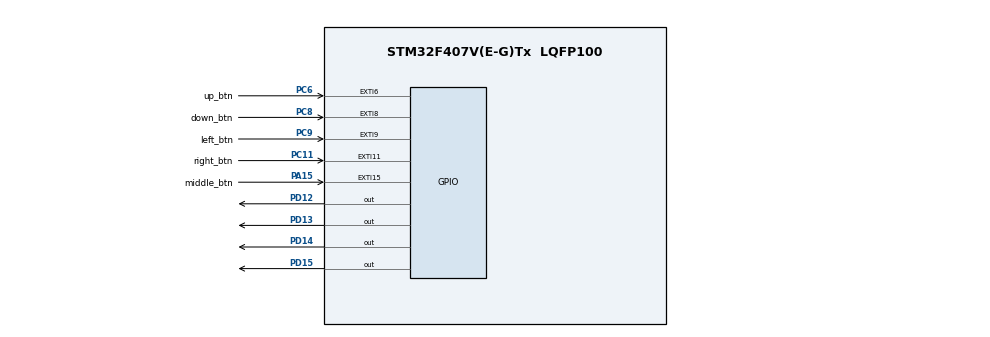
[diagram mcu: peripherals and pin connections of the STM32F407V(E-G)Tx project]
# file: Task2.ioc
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Mcu.Family=STM32F4
Mcu.Name=STM32F407V(E-G)Tx
Mcu.Package=LQFP100
NVIC.EXTI15_10_IRQn=true\:0\:0\:false\:false\:true\:true\:true
NVIC.EXTI9_5_IRQn=true\:0\:0\:false\:false\:true\:true\:true
NVIC.PriorityGroup=NVIC_PRIORITYGROUP_4
PA15.GPIO_Label=middle_btn
PA15.GPIO_ModeDefaultEXTI=GPIO_MODE_IT_FALLING
PA15.Signal=GPXTI15
PC11.GPIO_Label=right_btn
PC11.GPIO_ModeDefaultEXTI=GPIO_MODE_IT_FALLING
PC11.Signal=GPXTI11
PC6.GPIO_Label=up_btn
PC6.GPIO_ModeDefaultEXTI=GPIO_MODE_IT_FALLING
PC6.Signal=GPXTI6
PC8.GPIO_Label=down_btn
PC8.GPIO_ModeDefaultEXTI=GPIO_MODE_IT_FALLING
PC8.Signal=GPXTI8
PC9.GPIO_Label=left_btn
PC9.GPIO_ModeDefaultEXTI=GPIO_MODE_IT_FALLING
PC9.Signal=GPXTI9
PD12.Signal=GPIO_Output
PD13.Signal=GPIO_Output
PD14.Signal=GPIO_Output
PD15.Signal=GPIO_Output
ProjectManager.HeapSize=0x200
ProjectManager.StackSize=0x400
ProjectManager.TargetToolchain=STM32CubeIDE
RCC.AHBFreq_Value=16000000
RCC.APB1Freq_Value=16000000
RCC.APB2Freq_Value=16000000
RCC.CortexFreq_Value=16000000
RCC.HSE_VALUE=25000000
RCC.HSI_VALUE=16000000
RCC.LSE_VALUE=32768
RCC.SYSCLKFreq_VALUE=16000000
RCC.VCOOutputFreq_Value=192000000
board=custom

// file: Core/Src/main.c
/* USER CODE BEGIN Header */
/**
  ******************************************************************************
  * @file           : main.c
  * @brief          : Main program body
  ******************************************************************************
  * @attention
  *
  * <h2><center>&copy; Copyright (c) 2021 STMicroelectronics.
  * All rights reserved.</center></h2>
  *
  * This software component is licensed by ST under Ultimate Liberty license
  * SLA0044, the "License"; You may not use this file except in compliance with
  * the License. You may obtain a copy of the License at:
  *                             www.st.com/SLA0044
  *
  ******************************************************************************
  */
/* USER CODE END Header */
#include "main.h"

void SystemClock_Config(void);
static void MX_GPIO_Init(void);

/* USER CODE BEGIN 0 */
int speed = 500;
int mode = 0;
int count = 0;

void HAL_GPIO_EXTI_Callback(uint16_t GPIO_Pin)
{
    if(GPIO_Pin == SW3_Pin)
    {
    	speed += 50;
    }
    if(GPIO_Pin == SW4_Pin)
	{
		speed -= 50;
	}
    if(speed < 50)
    	speed = 50;
    if(speed > 1000)
        speed = 1000;
    if(GPIO_Pin == SW1_Pin)
    {
    	mode = !mode;
    }
}

/* USER CODE END 0 */

int main(void)
{

  /* MCU Configuration--------------------------------------------------------*/

  /* Reset of all peripherals, Initializes the Flash interface and the Systick. */
  HAL_Init();

  /* Configure the system clock */
  SystemClock_Config();

  /* Initialize all configured peripherals */
  MX_GPIO_Init();

  /* Infinite loop */
  while (1)
  {

    /* USER CODE BEGIN 3 */
	  if(!mode)
	  {
		  HAL_GPIO_TogglePin(GPIOD, Red_Pin);
		  HAL_Delay(speed);
		  HAL_GPIO_TogglePin(GPIOD, Orange_Pin);
		  HAL_Delay(speed);
		  HAL_GPIO_TogglePin(GPIOD, Green_Pin);
		  HAL_Delay(speed);
		  HAL_GPIO_TogglePin(GPIOD, Blue_Pin);
		  HAL_Delay(speed);
	  }
	  else
	  {
		  if(count)
		  {
			  HAL_GPIO_TogglePin(GPIOD, Red_Pin);
			  HAL_GPIO_TogglePin(GPIOD, Green_Pin);
			  HAL_GPIO_TogglePin(GPIOD, Orange_Pin);
			  HAL_GPIO_TogglePin(GPIOD, Blue_Pin);
			  HAL_Delay(speed);
		  }
		  if(count)
		  {
			  HAL_GPIO_TogglePin(GPIOD, Orange_Pin);
			  HAL_GPIO_TogglePin(GPIOD, Blue_Pin);
			  HAL_Delay(speed);
		  }
		  count = !count;
	  }
  }
  /* USER CODE END 3 */
}

void SystemClock_Config(void)
{
  RCC_OscInitTypeDef RCC_OscInitStruct = {0};
  RCC_ClkInitTypeDef RCC_ClkInitStruct = {0};

  /** Configure the main internal regulator output voltage
  */
  __HAL_RCC_PWR_CLK_ENABLE();
  __HAL_PWR_VOLTAGESCALING_CONFIG(PWR_REGULATOR_VOLTAGE_SCALE1);
  /** Initializes the RCC Oscillators according to the specified parameters
  * in the RCC_OscInitTypeDef structure.
  */
  RCC_OscInitStruct.OscillatorType = RCC_OSCILLATORTYPE_HSI;
  RCC_OscInitStruct.HSIState = RCC_HSI_ON;
  RCC_OscInitStruct.HSICalibrationValue = RCC_HSICALIBRATION_DEFAULT;
  RCC_OscInitStruct.PLL.PLLState = RCC_PLL_ON;
  RCC_OscInitStruct.PLL.PLLSource = RCC_PLLSOURCE_HSI;
  RCC_OscInitStruct.PLL.PLLM = 8;
  RCC_OscInitStruct.PLL.PLLN = 50;
  RCC_OscInitStruct.PLL.PLLP = RCC_PLLP_DIV4;
  RCC_OscInitStruct.PLL.PLLQ = 7;
  if (HAL_RCC_OscConfig(&RCC_OscInitStruct) != HAL_OK)
  {
    Error_Handler();
  }
  /** Initializes the CPU, AHB and APB buses clocks
  */
  RCC_ClkInitStruct.ClockType = RCC_CLOCKTYPE_HCLK|RCC_CLOCKTYPE_SYSCLK
                              |RCC_CLOCKTYPE_PCLK1|RCC_CLOCKTYPE_PCLK2;
  RCC_ClkInitStruct.SYSCLKSource = RCC_SYSCLKSOURCE_PLLCLK;
  RCC_ClkInitStruct.AHBCLKDivider = RCC_SYSCLK_DIV1;
  RCC_ClkInitStruct.APB1CLKDivider = RCC_HCLK_DIV4;
  RCC_ClkInitStruct.APB2CLKDivider = RCC_HCLK_DIV2;

  if (HAL_RCC_ClockConfig(&RCC_ClkInitStruct, FLASH_LATENCY_0) != HAL_OK)
  {
    Error_Handler();
  }
}

static void MX_GPIO_Init(void)
{
  GPIO_InitTypeDef GPIO_InitStruct = {0};

  /* GPIO Ports Clock Enable */
  __HAL_RCC_GPIOD_CLK_ENABLE();
  __HAL_RCC_GPIOC_CLK_ENABLE();
  __HAL_RCC_GPIOA_CLK_ENABLE();

  /*Configure GPIO pin Output Level */
  HAL_GPIO_WritePin(GPIOD, Green_Pin|Orange_Pin|Red_Pin|Blue_Pin, GPIO_PIN_RESET);

  /*Configure GPIO pins : Green_Pin Orange_Pin Red_Pin Blue_Pin */
  GPIO_InitStruct.Pin = Green_Pin|Orange_Pin|Red_Pin|Blue_Pin;
  GPIO_InitStruct.Mode = GPIO_MODE_OUTPUT_PP;
  GPIO_InitStruct.Pull = GPIO_NOPULL;
  GPIO_InitStruct.Speed = GPIO_SPEED_FREQ_LOW;
  HAL_GPIO_Init(GPIOD, &GPIO_InitStruct);

  /*Configure GPIO pins : SW3_Pin SW4_Pin */
  GPIO_InitStruct.Pin = SW3_Pin|SW4_Pin;
  GPIO_InitStruct.Mode = GPIO_MODE_IT_FALLING;
  GPIO_InitStruct.Pull = GPIO_NOPULL;
  HAL_GPIO_Init(GPIOC, &GPIO_InitStruct);

  /*Configure GPIO pin : SW1_Pin */
  GPIO_InitStruct.Pin = SW1_Pin;
  GPIO_InitStruct.Mode = GPIO_MODE_IT_FALLING;
  GPIO_InitStruct.Pull = GPIO_NOPULL;
  HAL_GPIO_Init(SW1_GPIO_Port, &GPIO_InitStruct);

  /* EXTI interrupt init*/
  HAL_NVIC_SetPriority(EXTI9_5_IRQn, 0, 0);
  HAL_NVIC_EnableIRQ(EXTI9_5_IRQn);

  HAL_NVIC_SetPriority(EXTI15_10_IRQn, 0, 0);
  HAL_NVIC_EnableIRQ(EXTI15_10_IRQn);

}

void HAL_TIM_PeriodElapsedCallback(TIM_HandleTypeDef *htim)
{
  if (htim->Instance == TIM1) {
    HAL_IncTick();
  }
}

void Error_Handler(void)
{
  __disable_irq();
  while (1)
  {
  }
}

/************************ (C) COPYRIGHT STMicroelectronics *****END OF FILE****/
